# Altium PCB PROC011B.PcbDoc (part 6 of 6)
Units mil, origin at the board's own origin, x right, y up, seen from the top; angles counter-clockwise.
Board outline 3304 x 2569 mil, 6 copper layers (TOP, L2-GND1, L3-GND/SIG, L4-GND/SIG, L5-GND2, BOTTOM), stack 55.77 mil thick; 376 components, 289 nets, 1284 pads, 1755 vias.

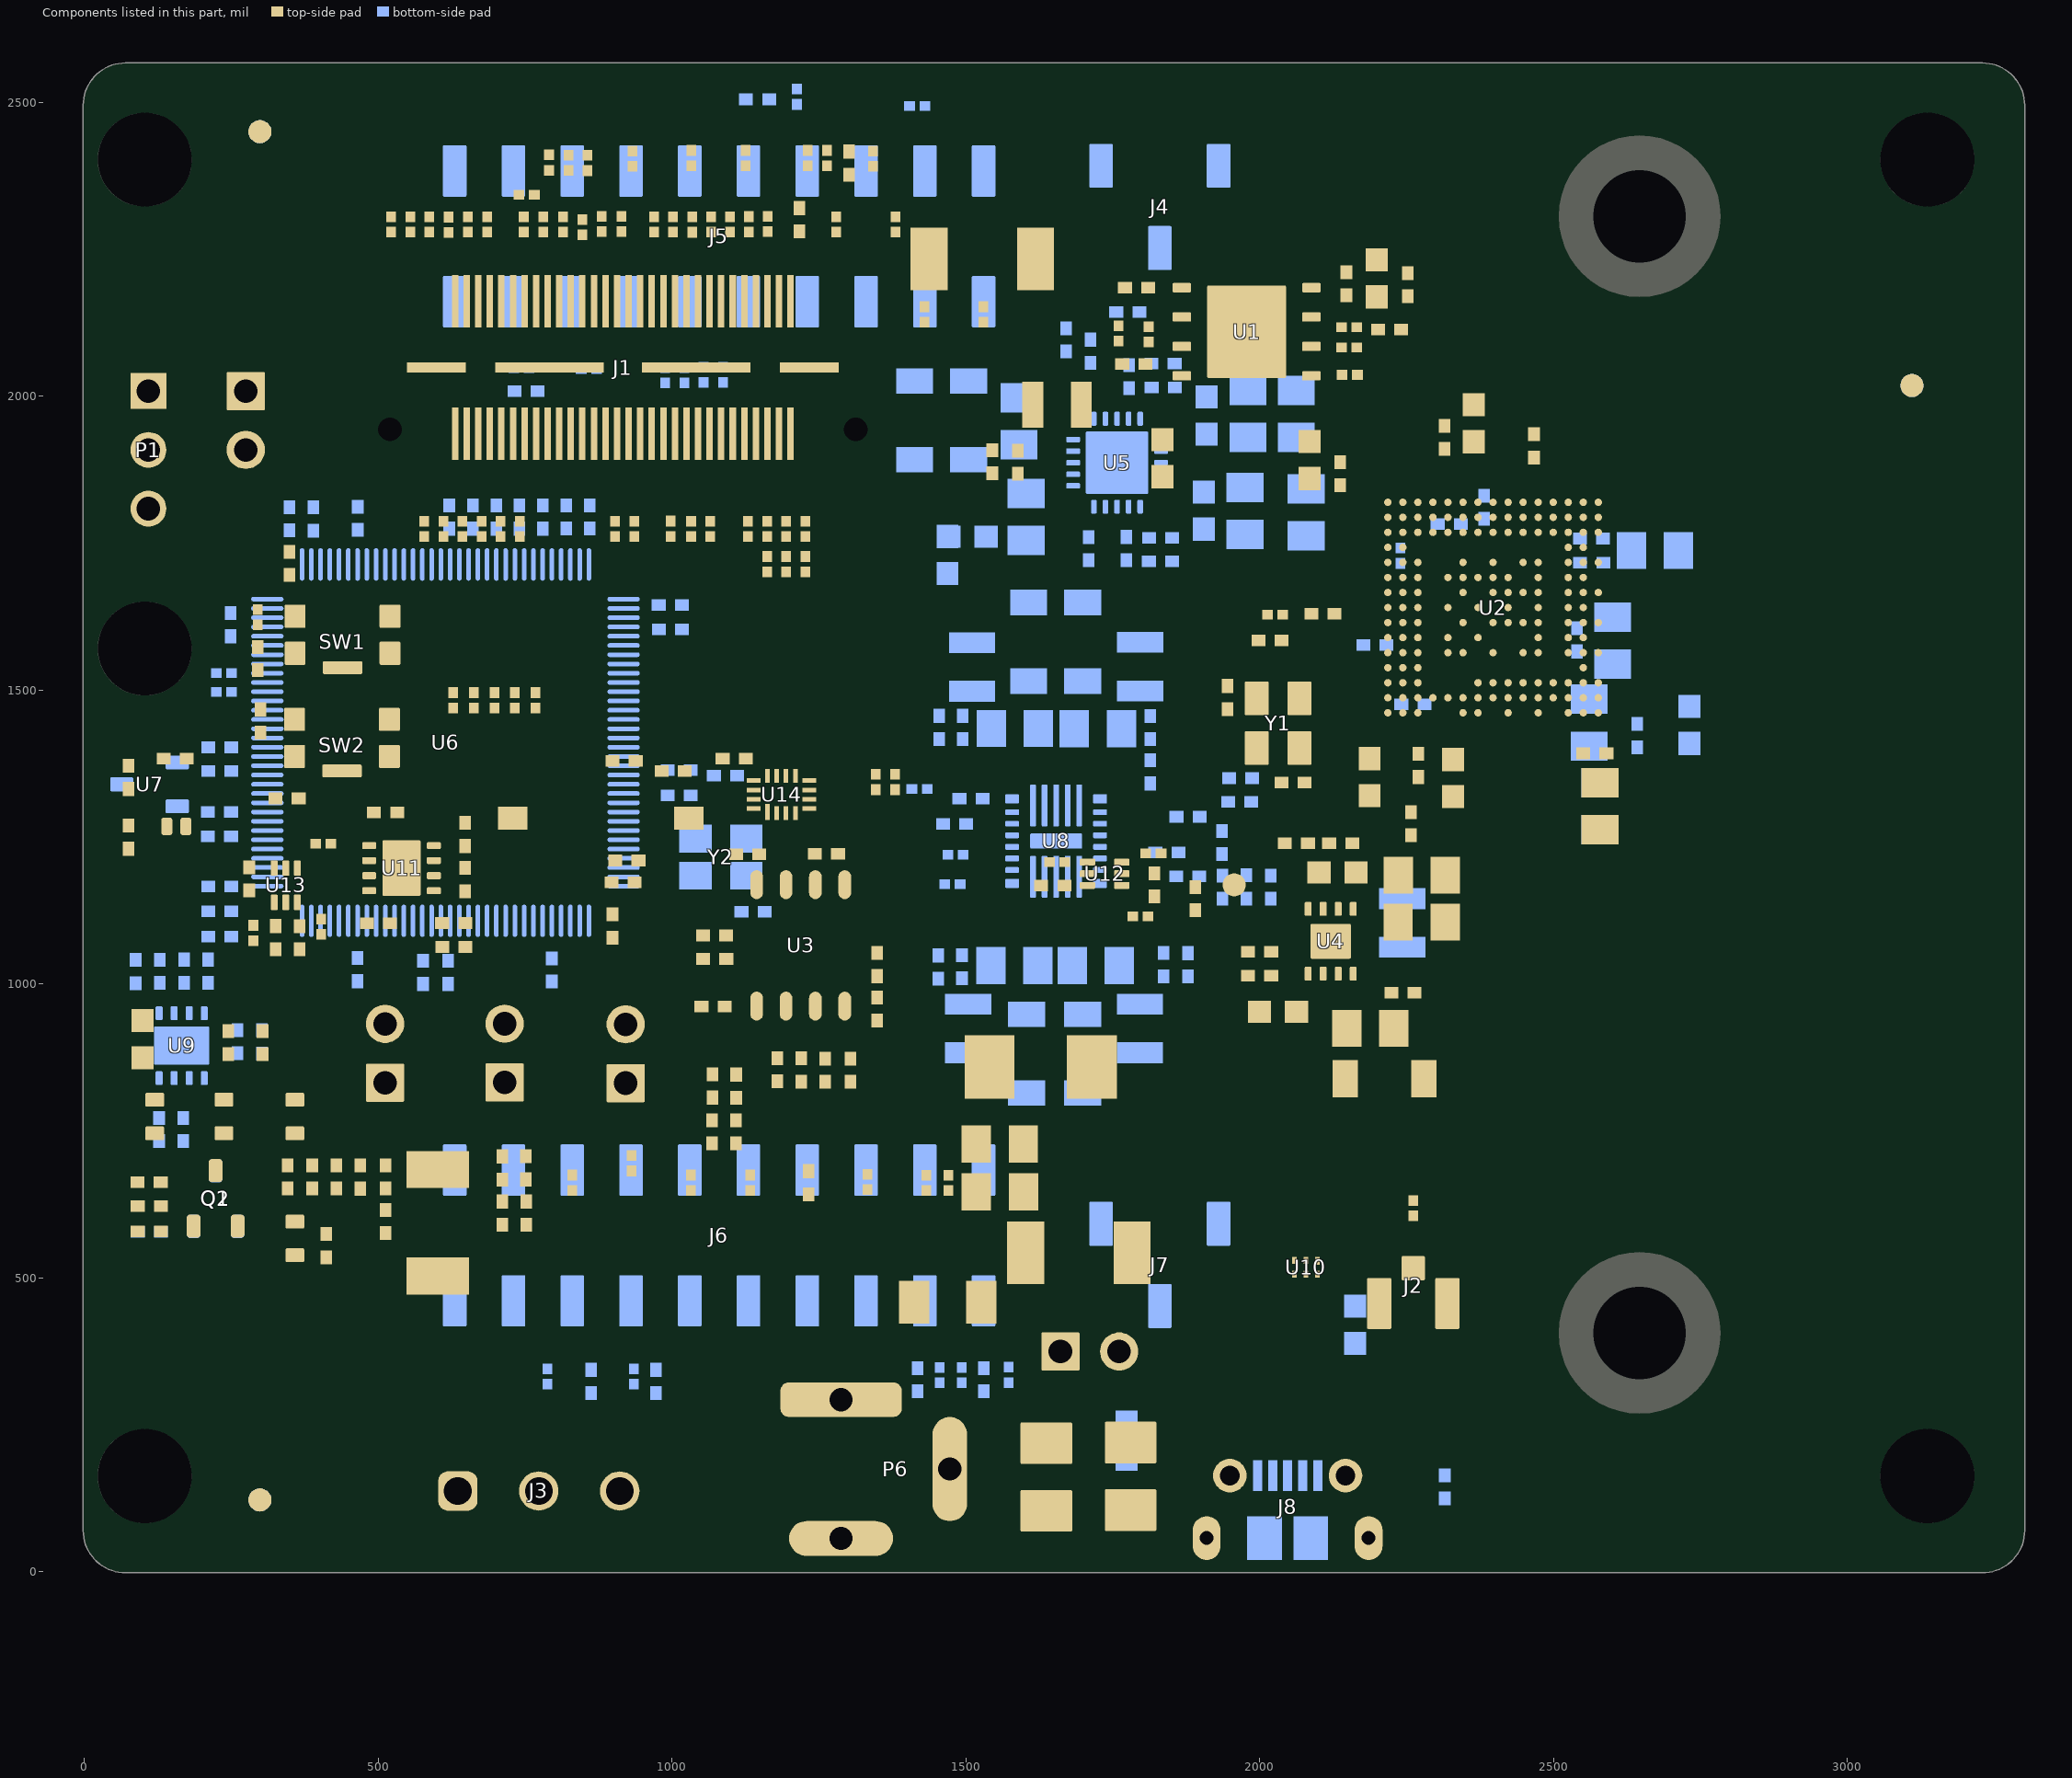
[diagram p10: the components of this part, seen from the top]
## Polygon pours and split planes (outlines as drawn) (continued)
NetR42_2 on TOP "TOP-UNNAMED_41_RESISTOR_I116_2" (solid, pour order 971): 1894.98,2096.48 1842.88,2096.48 1842.88,2072.88 1894.98,2072.88 1894.98,2096.48
NetR44_1 on TOP "TOP-UNNAMED_41_RESISTOR_I117_1" (solid, pour order 970): 2112.88,2096.48 2060.78,2096.48 2060.78,2072.88 2112.88,2072.88 2112.88,2096.48
NetR45_1 on TOP "TOP-UNNAMED_41_RESISTOR_I118_1" (solid, pour order 969): 2112.88,2046.48 2060.78,2046.48 2060.78,2022.88 2112.88,2022.88 2112.88,2046.48
NetR39_2 on TOP "TOP-UNNAMED_41_RESISTOR_I119_2" (solid, pour order 968): 1894.98,2146.48 1842.88,2146.48 1842.88,2122.88 1894.98,2122.88 1894.98,2146.48
NetR40_1 on TOP "TOP-UNNAMED_41_RESISTOR_I120_1" (solid, pour order 967): 2112.88,2146.48 2060.78,2146.48 2060.78,2122.88 2112.88,2122.88 2112.88,2146.48
NetJ1_1 on TOP "TOP-UNNAMED_43_QSH03001XD_I1_1" (solid, pour order 966): 466 vertices, not listed, extent 1177.39,1891 1453.7,2296
NetF1_2 on TOP "TOP-UNNAMED_39_FUSE_I161_1" (solid, pour order 965): 146 vertices, not listed, extent 1188.75,269 1438.25,500
MCU_5V on TOP "TOP-MCU_5V" (solid, pour order 962): 124 vertices, not listed, extent 521.77,668 690.75,772
PMIC_2V3 on TOP "TOP-PMIC_2V3" (solid, pour order 957): 258 vertices, not listed, extent 1843.65,791.5 2266.05,1059.2
NetC85_2 on TOP "TOP-UNNAMED_7_CAPNONPOLARIZED_I5_2" (solid, pour order 954): 194 vertices, not listed, extent 384.65,1079 496.19,1218
NetC26_1 on TOP "TOP-UNNAMED_39_CAPPOLARIZED_I74_1" (solid, pour order 953): 340 vertices, not listed, extent 1471.05,182.8 1838.25,913.5
TX1 on TOP "TOP-TX1" (solid, pour order 1042): 38 vertices, not listed, extent 2736.95,1172.87 3184.98,1231.93
TX2 on TOP "TOP-TX2" (solid, remove dead copper, pour order 1043): 38 vertices, not listed, extent 2736.95,873.67 3184.98,932.73
PMIC_1V2 on TOP "TOP-PMIC_1V2" (solid, pour order 979): 40 vertices, not listed, extent 1988.35,1837.9 2151.05,1900.5
GND on TOP "TOP-GND 5" (solid, pour order 981): 38 vertices, not listed, extent 2736.95,1823.37 3184.98,1882.43
GND on TOP "TOP-GND 4" (solid, pour order 978): 38 vertices, not listed, extent 2736.95,1449.37 3184.98,1508.43
RX1 on TOP "TOP-RX1" (solid, pour order 952): 38 vertices, not listed, extent 2736.95,1748.57 3184.98,1807.63
RX2 on TOP "TOP-RX2" (solid, pour order 950): 38 vertices, not listed, extent 2736.95,1673.77 3184.98,1732.83
RX3 on TOP "TOP-RX3" (solid, pour order 949): 38 vertices, not listed, extent 2736.95,1598.97 3184.98,1658.03
RX4 on TOP "TOP-RX4" (solid, pour order 948): 38 vertices, not listed, extent 2736.95,1524.17 3184.98,1583.23
no net on TOP "Top Layer-No Net" (solid, pour order 951): 1734.28,2432.55 1746.09,2432.55 1769.71,2431.96 2395.15,2431.96 2418.77,2432.55 2430.58,2432.55 2430.58,2438.45 2418.77,2438.45 2395.15,2439.04 1769.71,2439.04 1746.09,2438.45 1734.28,2438.45
no net on TOP "Top Layer-No Net" (solid, pour order 956): 2211.13,2344.45 2211.13,2350.35 2222.94,2350.35 2246.56,2350.94 2394.35,2350.94 2417.97,2350.35 2429.78,2350.35 2429.78,2344.45 2417.97,2344.45 2394.35,2343.86 2246.56,2343.86 2222.94,2344.45
GND on TOP "TOP-GND 1" (solid, remove dead copper, pour order 1007): 2460.75,2487 2460.75,2309 2076.75,2309 2076.75,2382 1698.75,2382 1698.75,2487 2460.75,2487
GND on L4-GND/SIG "L4-GND 4" (solid, pour order 1023): 1170 vertices, not listed, extent 1011,2201.12 1728.04,2476.59
GND on L4-GND/SIG "L4-GND 3" (solid, remove dead copper, pour order 1022): 2496 vertices, not listed, extent 16,16 3284,2549
GND on L4-GND/SIG "L4-GND 1" (solid, pour order 1020): 840 vertices, not listed, extent 2279.76,1480.82 2511.89,1757.58
GND on L4-GND/SIG "L4-GND" (solid, pour order 1019): 555 vertices, not listed, extent 486.77,2124.33 1041.63,2468.58
5V_IN on L4-GND/SIG "L4-5V_IN" (solid, remove dead copper, pour order 997): 1026 vertices, not listed, extent 437.25,327 1727.75,2363.5
AR_1V8 on L4-GND/SIG "L4-AR_1V8" (solid, pour order 986): 679 vertices, not listed, extent 2127.75,1077.15 2619.75,1752
PMIC_1V2 on L4-GND/SIG "L4-PMIC_1V2" (solid, pour order 984): 1509 vertices, not listed, extent 1750.75,1574 2517.75,2258.4
NetC85_2 on L4-GND/SIG "L4-UNNAMED_7_CAPNONPOLARIZED_I5_2" (solid, pour order 955): 96 vertices, not listed, extent 371.65,1146.2 422.25,1236.1
5V_UNREG on L4-GND/SIG "POWER2-No Net" (solid, remove dead copper, pour order 1046): 44 vertices, not listed, extent 1441.77,315 1865.48,1542.5
GND on L4-GND/SIG "Top Layer-No Net" (solid, pour order 116): 43 vertices, not listed, extent 1376.03,1265.26 1898.12,2227.86
GND on BOTTOM "BOTTOM-GND 4" (solid, remove dead copper, pour order 1035): 2173 vertices, not listed, extent 1878.77,15.7 3284.85,2549.9
GND on BOTTOM "BOTTOM-GND 7" (solid, pour order 1040): 307 vertices, not listed, extent 1568.8,1267.5 1736.9,1546
GND on BOTTOM "BOTTOM-GND 6" (solid, pour order 1039): 239 vertices, not listed, extent 1567.7,919.3 1734.3,1218.3
GND on BOTTOM "BOTTOM-GND 5" (solid, pour order 1037): 98 vertices, not listed, extent 1882.75,1982.35 2102.75,2147.5
GND on BOTTOM "BOTTOM-GND 3" (solid, pour order 1034): 510 vertices, not listed, extent 1703,307 2093.73,726.5
GND on BOTTOM "BOTTOM-GND 2" (solid, pour order 1033): 124 vertices, not listed, extent 1364.75,1971.5 1621.05,2069.85
GND on BOTTOM "BOTTOM-GND 1" (solid, pour order 1013): 2497.25,2153.5 2796.25,2153.5 2796.25,2455.5 2497.25,2455.5 2497.25,2153.5
GND on BOTTOM "BOTTOM-GND" (solid, pour order 1008): 21 vertices, not listed, extent 2421.7,31.02 3277.75,827.5
5V_UNREG on BOTTOM "BOTTOM-5V_UNREG 3" (solid, pour order 1005): 200 vertices, not listed, extent 1525.15,1267.5 1619.3,1475.26
5V_UNREG on BOTTOM "BOTTOM-5V_UNREG 2" (solid, pour order 1004): 209 vertices, not listed, extent 1687.75,1267.5 1787.85,1475.66
5V_UNREG on BOTTOM "BOTTOM-5V_UNREG 1" (solid, pour order 1003): 202 vertices, not listed, extent 1686.8,1002.3 1813.8,1218.5
5V_UNREG on BOTTOM "BOTTOM-5V_UNREG" (solid, remove dead copper, pour order 1002): 183 vertices, not listed, extent 1514.45,1002.3 1620.75,1218.3
PMICOUT_3V3 on BOTTOM "BOTTOM-PMICOUT_3V3" (solid, pour order 999): 176 vertices, not listed, extent 1453.77,1563.04 1642.75,1711.5
AR_1P3_RF1 on BOTTOM "BOTTOM-AR_1P3_RF1" (solid, pour order 992): 937 vertices, not listed, extent 1821.75,1607 2812.73,1963.7
AR_1P3_RF2 on BOTTOM "BOTTOM-AR_1P3_RF2" (solid, pour order 990): 1059 vertices, not listed, extent 1818.8,1431.4 2987.75,2118
AR_1V8 on BOTTOM "BOTTOM-AR_1V8 1" (solid, pour order 988): 124 vertices, not listed, extent 2147.75,1120 2286.65,1256.3
AR_1V8 on BOTTOM "BOTTOM-AR_1V8" (solid, pour order 987): 91 vertices, not listed, extent 2526.75,1593 2629.75,1638.98
PMIC_1V2 on BOTTOM "BOTTOM-PMIC_1V2" (solid, pour order 983): 299 vertices, not listed, extent 1663,1563 1950.75,1709.25
AR_VOUT_PA on BOTTOM "BOTTOM-AR_VOUT_PA" (solid, pour order 976): 138 vertices, not listed, extent 2539.75,1315 2755.75,1427
PMIC_1V8 on BOTTOM "BOTTOM-PMIC_1V8" (solid, remove dead copper, pour order 973): 1183 vertices, not listed, extent 1339.97,801.5 1702.75,1952.5
MCU_5V on BOTTOM "BOTTOM-MCU_5V 1" (solid, pour order 964): 98 vertices, not listed, extent 1868.75,510 1993.75,651
MCU_5V on BOTTOM "BOTTOM-MCU_5V" (solid, pour order 961): 149 vertices, not listed, extent 517.75,626.5 686.75,759.5
PMIC_2V3 on BOTTOM "BOTTOM-PMIC_2V3 1" (solid, pour order 960): 146 vertices, not listed, extent 2140.55,968.7 2284.45,1079.3
PMIC_2V3 on BOTTOM "BOTTOM-PMIC_2V3" (solid, pour order 958): 127 vertices, not listed, extent 1662.75,791 1947.35,900.66
GND on L3-GND/SIG "L3-GND 7" (solid, remove dead copper, pour order 1029): 3094 vertices, not listed, extent 16,16 3284,2549
GND on L3-GND/SIG "L3-GND 6" (solid, pour order 1028): 2622 vertices, not listed, extent 1431.33,501.13 2744.73,1845.59
GND on L3-GND/SIG "L3-GND 5" (solid, pour order 1027): 744 vertices, not listed, extent 991.89,593.02 1910.98,1006.2
GND on L3-GND/SIG "L3-GND 4" (solid, pour order 1026): 147 vertices, not listed, extent 231.09,1463.5 468.73,1691.74
GND on L3-GND/SIG "L3-GND 3" (solid, pour order 1025): 344 vertices, not listed, extent 1505.88,1776.02 1989.21,2041.98
GND on L3-GND/SIG "L3-GND 2" (solid, pour order 1024): 146 vertices, not listed, extent 1858.06,1991.53 2249.71,2152.58
GND on L3-GND/SIG "L3-GND 1" (solid, pour order 1012): 2487.75,562.5 2787.75,562.5 2787.75,262.5 2487.75,262.5 2487.75,562.5
GND on L3-GND/SIG "L3-GND" (solid, pour order 1011): 2507.75,2437.5 2777.75,2437.5 2777.75,2182.5 2597.75,2182.5 2507.75,2272.5 2507.75,2437.5
MCU_5V on L3-GND/SIG "L3-MCU_5V" (solid, pour order 963): 517 vertices, not listed, extent 507.75,406 1962.23,755.48
GND on L2-GND1 "L2-GND 1" (solid, pour order 1010): 2527.25,529.5 2527.25,282.5 2772.25,282.5 2772.25,529.5 2527.25,529.5
GND on L2-GND1 "L2-GND" (solid, pour order 1009): 2524.75,2427 2524.75,2180 2769.75,2180 2769.75,2427 2524.75,2427
GND on L2-GND1 "L5-GND" (solid, remove dead copper, pour order 1018): 553 vertices, not listed, extent 16,16 3284,2549
GND on L5-GND2 "L5-GND" (solid, remove dead copper, pour order 1017): 553 vertices, not listed, extent 16,16 3284,2549
no net on Mechanical 6 Ass bot (solid): 3150.95,2033.2 ccw(c3108.95,2033.2) 3108.95,2075.2 ccw(c3108.95,2033.2) 3066.95,2033.2 ccw(c3108.95,2033.2) 3108.95,1991.2 ccw(c3108.95,2033.2) 3150.95,2033.2
no net on Mechanical 6 Ass bot (solid): 340.75,122 ccw(c298.75,122) 298.75,164 ccw(c298.75,122) 256.75,122 ccw(c298.75,122) 298.75,80 ccw(c298.75,122) 340.75,122
no net on Mechanical 6 Ass bot (solid): 340.75,2450 ccw(c298.75,2450) 298.75,2492 ccw(c298.75,2450) 256.75,2450 ccw(c298.75,2450) 298.75,2408 ccw(c298.75,2450) 340.75,2450
no net on Mechanical 5 Ass top (solid): 340.75,2450 ccw(c298.75,2450) 298.75,2492 ccw(c298.75,2450) 256.75,2450 ccw(c298.75,2450) 298.75,2408 ccw(c298.75,2450) 340.75,2450
no net on Mechanical 5 Ass top (solid): 3152.65,2018.46 ccw(c3110.65,2018.46) 3110.65,2060.46 ccw(c3110.65,2018.46) 3068.65,2018.46 ccw(c3110.65,2018.46) 3110.65,1976.46 ccw(c3110.65,2018.46) 3152.65,2018.46
no net on Mechanical 5 Ass top (solid): 340.75,122 ccw(c298.75,122) 298.75,164 ccw(c298.75,122) 256.75,122 ccw(c298.75,122) 298.75,80 ccw(c298.75,122) 340.75,122

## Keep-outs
TOP:
  circle w10: c102.75,2402.5 r92.09
  circle w10: c102.75,1570.6 r92.09
  circle w10: c102.75,162.5 r92.09
  circle w10: c3136.31,2402.5 r92.09
  circle w10: c3136.31,162.5 r92.09
L2-GND1:
  circle w10: c3136.31,2402.5 r100.82
  circle w10: c3136.31,162.5 r100.82
  circle w10: c3136.31,2402.5 r100.82
  circle w10: c1312.65,1943.64 r44.95
  circle w10: c520.13,1943.64 r44.95
L3-GND/SIG:
  circle w10: c3136.31,162.5 r100.82
  circle w10: c3136.31,2402.5 r100.82
L4-GND/SIG:
  circle w10: c1312.65,1943.64 r44.95
  circle w10: c3136.31,162.5 r100.82
  circle w10: c3136.31,2402.5 r100.82
L5-GND2:
  circle w10: c1312.65,1943.64 r44.95
  circle w10: c520.13,1943.64 r44.95
  circle w10: c3136.31,2402.5 r100.82
  circle w10: c3136.31,162.5 r100.82
BOTTOM:
  circle w10: c3136.31,162.5 r92.09
  circle w10: c3136.31,2402.5 r92.09
  circle w1: c3110.08,2018.14 r44
Keep-Out Layer:
  text "KEEP OUT LAYER" at -1318.01,-1032.33 h75

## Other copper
TOP:
  text "TOP" at -1316.15,-1038.69 h75
L2-GND1:
  text "LAYER-2 GND1" at -1293.22,-1034.39 h75
L3-GND/SIG:
  text "LAYER-3 GND/SIGNAL" at -1349.73,-1034.31 h75
L4-GND/SIG:
  text "LAYER-4 GND/SIGNAL" at -1322.23,-1041.27 h75
L5-GND2:
  text "LAYER-5 GND2" at -1308.33,-1043.01 h75
BOTTOM:
  text "BOTTOM" at -1318.46,-1042.03 h75

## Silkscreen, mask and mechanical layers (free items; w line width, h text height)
Top Overlay:
  lines w10: 176.28,1919.69 179.6,1919.69 193.53,1905.76 193.53,1794.32 187.71,1800.14 200.17,1800.14 194.35,1794.32
  lines w30: 1378.75,904.5 1378.75,818 1459.85,818 ; 1378.75,1094.5 1378.75,1274.5 ; 1382.75,1830 1382.75,2242 ; 1700.75,2258 2146.75,2258 ; 1786.25,818 2088.75,818 ; 2268.75,2258 2474.75,2258 ; 2770.75,1968 2770.75,2182
  text "HD_CONN" at 467.92,2015.1 h30 r90
  text "VPP_1P7" at 381.32,1862.65 h30 r90
  text "1642-EVM" at 813.79,1694.33 h30
  text "GND" at 209.45,1680.5 h30 r90
  text "PROC011" at 775,1637.52 h30
  text "REV B" at 969.45,1635.95 h30
  text "GPIO1" at 620.25,1543 h30 r90
  text "ON" at 1079.14,1311 h30 r90
  text "NRST" at 615.01,1295.07 h30 r90
  text "SPI" at 709,1164 h30 r90
  text "CAN" at 1079.14,1153 h30 r90
  text "SOP0" at 1025.49,883.72 h30 r90
  text "5V" at 385.25,854.5 h30 r90
  text "NERR_OUT" at 211.42,848.5 h30 r90
  text "SOP1" at 821.68,840.86 h30 r90
  text "SOP2" at 615.55,835.13 h30 r90
  text "NRST" at 404.16,399.06 h30 r90
  text "5V_IN" at 1194.75,354 h30 r90
  text "GND" at 790.25,294 h30 r90
  text "CAN_L" at 1066.42,227.5 h30 r90
  text "CAN_H" at 542.42,226.5 h30 r90
  text "USB" at 2011.93,198.27 h30
  text "SILKSCREEN TOP" at -1339.97,-1029.03 h60
Bottom Overlay:
  drawing of 8192 lines, arcs and shapes, not listed
  text "GND" at 1745.25,2556 h30 r90
  text "GND" at 1845.25,2556 h30 r90
  text "3V3" at 1943.47,2549.66 h30 r90
  text "GND" at 596.45,2529.6 h30 r90
  text "20" at 1634.19,2423.68 h30 r90
  text "2" at 552.36,2404.47 h30 r90
  text "19" at 1638.64,2210.67 h30 r90
  text "1" at 544.91,2180.78 h30 r90
  text "P1" at 132.79,2073.5 h30
  text "P7" at 396.41,2020 h30
  text "P4" at 955.85,1005.8 h30
  text "P3" at 537.9,1001.27 h30
  text "P2" at 736.23,1000.15 h30
  text "GND" at 790.25,886 h30 r90
  text "GND" at 1845.25,776 h30 r90
  text "GND" at 1735.25,771 h30 r90
  text "20" at 1641.82,729.19 h30 r90
  text "2" at 553.44,705.94 h30 r90
  text "19" at 1656.65,524.84 h30 r90
  text "1" at 545.99,482.25 h30 r90
  text "P6" at 1317.41,338.79 h30
  text "P5" at 1877.7,327.72 h30
  text "J3" at 538.18,135.69 h30
  text "SILKSCREEN BOTTOM" at -1330.97,-1032.41 h75
Top Paste:
  text "SOLDERPASTE TOP" at -1322.76,-1029.77 h75
Bottom Paste:
  text "SOLDERPASTE BOTTOM" at -1315.43,-1031.21 h75
Top Solder:
  text "SOLDERMASK TOP" at -1325.23,-1033.37 h75
Bottom Solder:
  text "SOLDERMASK BOTTOM" at -1292.25,-1013.98 h75
OUTLINE:
  lines w4: 0,70 ccw(c70,70) 70,0 3230,0 ccw(c3230,70) 3300,70 3300,2495 ccw(c3230,2495) 3230,2565 70,2565 ccw(c70,2495) 0,2495 0,70
Board Dimensions:
  text "AT 4 PLACES" at -810,-280 h75
Mechanical 5 Ass top:
  lines w6: 163,2270 163,2286 174,2297 355,2297 405,2247 741,2247 747,2253 747,2256 ; 355.14,2202 420,2202 435,2217 897.05,2217 912,2231.95 912,2254 ; 974,2330 974,2349.96 985.04,2361 1276.02,2361 1291.02,2346 1361,2346 1376,2361 1376,2381 1391,2396 ; 1162.65,2337 1162.65,2337.65 1171,2346 1256.78,2346 1269.78,2333 1574,2333 1604,2363 1604,2371 ; 2111,2139 2111,2127.39 2113.39,2125
  lines w10: -2151.07,-1099.34 4448.93,-1099.34 ; -2151.07,-896 4450.93,-896 ; -2151.07,-692.67 -2151.07,-1302.67 1853.93,-1302.67 4450.93,-1302.67 4450.93,-692.67 -2150.57,-692.67 -2150.57,-1302.67 -575.07,-1302.67 ; 313.93,-1302.67 313.93,-692.67 ; 1580.93,-896 1580.93,-692.67 ; 2420.93,-896 2420.93,-692.67 ; 3042.93,-1309.17 3042.93,-1106.34
  text "COMPONENTS MARKED 'DNP' SHOULD NOT BE POPULATED." at -1592.26,2897.89 h60
  text "ASSEMBLY VARIANT:" at -1592.76,2782.39 h60
  text ".VariantName" at -556.76,2782.39 h60
  text "PCB VIEWED FROM TOP SIDE" at -2087.57,-824.84 h60
  text "BOARD #:" at 388.93,-824.84 h60
  text ".PRJ_Number" at 934.43,-824.84 h60
  text "REV:" at 1778.93,-824.84 h60
  text ".PCB_Rev" at 2070.43,-824.84 h60
  text "SVN REV:" at 2616.93,-824.84 h60
  text ".VersionControl_RevNumber" at 3122.93,-824.84 h60
  text "Assembly TOP" at -1818.81,-1016.17 h60
  text "TID #:" at 388.93,-1028.17 h60
  text ".TID" at 934.43,-1028.17 h60
  text "PLOT NAME =" at -2087.57,-1233.51 h60
  text ".plot_File_Name" at -1282.07,-1233.51 h35
  text "GENERATED    :" at 390.93,-1233.51 h60
  text ".Print_Date" at 1260.43,-1233.51 h60
  text ".Print_Time" at 1989.43,-1233.51 h60
  text "TEXAS INSTRUMENTS" at 3253.93,-1233.51 h60
Mechanical 6 Ass bot:
  lines w10: -2151.07,-896 4450.93,-896 ; -2149.07,-1099.34 4450.93,-1099.34 ; -743.07,-1309.17 -743.07,-1106.34 ; -121.07,-896 -121.07,-692.67 ; 718.93,-896 718.93,-692.67 ; 1985.93,-1302.67 1985.93,-692.67 ; 2874.93,-1302.67 4450.43,-1302.67 4450.43,-692.67 -2151.07,-692.67 -2151.07,-1302.67 445.93,-1302.67 4450.93,-1302.67 4450.93,-692.67
  text "COMPONENTS MARKED 'DNP' SHOULD NOT BE POPULATED." at 4243.43,-486.67 h60
  text ".VariantName" at 3199.43,-602.67 h60
  text "ASSEMBLY VARIANT:" at 4238.43,-602.67 h60
  text ".VersionControl_RevNumber" at -823.07,-824.84 h60
  text "SVN REV:" at -317.07,-824.84 h60
  text ".PCB_Rev" at 229.43,-824.84 h60
  text "REV:" at 520.93,-824.84 h60
  text ".PRJ_Number" at 1365.43,-824.84 h60
  text "BOARD #:" at 1910.93,-824.84 h60
  text "PCB VIEWED FROM BOTTOM SIDE" at 4387.43,-824.84 h60
  text ".TID" at 1365.43,-1028.17 h60
  text "TID #:" at 1910.93,-1028.17 h60
  text "ASSEMBLY BOTTOM" at 4003,-1028 h60
  text "TEXAS INSTRUMENTS" at -954.07,-1233.51 h60
  text ".Print_Time" at 310.43,-1233.51 h60
  text ".Print_Date" at 1039.43,-1233.51 h60
  text "GENERATED    :" at 1908.93,-1233.51 h60
  text ".plot_File_Name" at 3581.93,-1233.51 h35
  text "PLOT NAME =" at 4387.43,-1233.51 h60
M9 Title Sheet:
  lines w10: -2351.2,871.62 -2151.2,871.62 ; -2351.2,3246.62 -2151.2,3246.62 ; -2351.2,5621.62 -2151.2,5621.62 ; 148.8,-1503.38 148.8,-1303.38 ; 148.8,7796.62 148.8,7996.62 ; 2648.8,-1503.38 2648.8,-1303.38 ; 2648.8,7796.62 2648.8,7996.62 ; 4461.3,-1303.38 4461.3,-693.38 9443.8,-693.38 ; 5148.8,-1503.38 5148.8,-1303.38 ; 5148.8,7796.62 5148.8,7996.62 ; 7648.8,-1503.38 7648.8,-1303.38 ; 7648.8,7796.62 7648.8,7996.62 ; 9443.8,-1303.38 9443.8,-693.38 ; 9443.8,-993.38 12443.8,-993.38 ; 9443.8,-393.38 12443.8,-393.38 ; 9444.8,200.62 12444.8,200.62 ; 10148.8,-1503.38 10148.8,-1303.38 ; 10148.8,7796.62 10148.8,7996.62 ; 10948.8,-1293.38 10948.8,-693.38 ; 12443.8,-693.38 9443.8,-693.38 ; 12443.8,-93.38 9443.8,-93.38 ; 12448.8,-103.38 12448.8,-1303.38 ; 12448.8,701.12 9444.8,701.12 9443.8,701.12 9443.8,200.62 9443.8,-93.38 ; 12448.8,871.62 12648.8,871.62 ; 12448.8,3246.62 12648.8,3246.62 ; 12448.8,5621.62 12648.8,5621.62 ; 9443.8,-693.38 9443.8,-93.38 ; 12448.8,-1303.38 12448.8,7796.62 -2151.2,7796.62 -2151.2,-1303.38 12448.8,-1303.38 ; -2351.2,-1503.38 -2351.2,7996.62 12648.8,7996.62 12648.8,-1503.38 -2351.2,-1503.38
  text "1" at -1119.86,7866.62 h70
  text "2" at 1375.8,7866.62 h70
  text "3" at 3865.14,7866.62 h70
  text "4" at 6371.81,7866.62 h70
  text "5" at 8870.8,7866.62 h70
  text "6" at 11375.8,7866.62 h70
  text "A" at -2276.2,6723.62 h70
  text "A" at 12523.8,6723.62 h70
  text "B" at -2276.2,4343.62 h70
  text "B" at 12523.8,4343.62 h70
  text "C" at -2276.2,1968.62 h70
  text "C" at 12523.8,1968.62 h70
  text "PROJECT TITLE:" at 9483.8,107.62 h45
  text ".PRJ_Title" at 9533.8,-25.71 h50
  text "DESIGNED FOR:" at 9483.8,-193.38 h45
  text ".PRJ_Customer" at 9533.8,-333.38 h70
  text "D" at -2276.2,-401.38 h70
  text "D" at 12523.8,-401.38 h70
  text "FILE NAME:" at 9483.8,-493.38 h45
  text ".PCB_File_Name_No_Path" at 9533.8,-613.38 h70
  text "Texas Instruments (TI) and/or its licensors do not warrant the accuracy or completeness of this specification" at 4514.3,-775.22 h45
  text "ENGINEER:" at 9483.8,-783.38 h45
  text "LAYOUT BY:" at 10988.8,-783.38 h45
  text "or any information contained therein. TI and/or its licensors do not warrant that this design will meet" at 4469.31,-887.88 h45
  text ".PRJ_Engineer" at 9533.8,-938.37 h70
  text ".PCB_Layout" at 11039.3,-938.37 h70
  text "the specifications, will be suitable for your application or fit for any particular purpose, or will operate in" at 4469.31,-1000.55 h45
  text "ALTIUM DESIGNER VERSION:" at 10988.8,-1093.38 h45
  text "an implementation. TI and/or its licensors do not warrant that the design is production worthy. You should" at 4469.31,-1113.21 h45
  text "completely validate and test your design implementation to confirm the system functionality for your application." at 4514.3,-1225.88 h45
  text ".print_Scale" at 9533.8,-1226.71 h70
  text ".Application_BuildNumber" at 11039.3,-1226.71 h70
  text "1" at -1119.86,-1433.38 h70
  text "2" at 1375.8,-1433.38 h70
  text "3" at 3865.14,-1433.38 h70
  text "4" at 6371.81,-1433.38 h70
  text "5" at 8870.8,-1433.38 h70
  text "6" at 11375.8,-1433.38 h70
LOGO_HOT:
  drawing of 189 lines, arcs and shapes, not listed
  text "DESIGN INFORMATION" at 10521.82,6186.29 h60
  text "MIL" at 11183,6056 h60
  text "MIN. TRACK WIDTH:" at 9877.26,6054.17 h60
  text "4" at 10973.5,6054.17 h60
  text "4" at 10965.36,5957.06 h60
  text "MIL" at 11182.26,5931 h60
  text "MIN. CLEARANCE:" at 9877.26,5930.04 h60
  text "MIL" at 11185,5807 h60
  text "MIN. VIA PAD SIZE:" at 9877.26,5805.92 h60
  text "13.77" at 10873,5798 h60
  text "0.05mm (2MIL)" at 10572.26,5676.02 h60
  text "MINIMUM ANNULAR RING" at 9548.03,5667.79 h60
  text "EXTERNAL" at 11280.26,5667.79 h60
  text "PER" at 9748.03,5557.67 h60
  text "IPC-D-275 CLASS 2 LEVEL C" at 9968.03,5557.66 h60
  text "MIL, HOLES" at 11456.26,5457.19 h60
  text "+/-" at 11063.8,5448.6 h60
  text "+/-" at 11917.8,5448.6 h60
  text "REGISTRATION TOLERANCES:" at 9548.03,5447.54 h60
  text "METAL" at 10747.8,5447.54 h60
  text "2" at 11324,5447.54 h60
  text "3" at 12157,5447.54 h60
  text "MIL" at 12273.26,5447.54 h60
  text "HOLE SIZE TOLERANCE (UNLESS OTHERWISE SPECIFIED):" at 9548.03,5349.22 h60
  text "+/-" at 11917.8,5346.35 h60
  text "3" at 12157,5345.29 h60
  text "MIL" at 12273.26,5345.29 h60
  text "MATERIAL:" at 9473.26,5207.64 h60
  text "FR-4 High Tg" at 10459.7,5079.12 h60
  text "X" at 11197.39,5075.36 h60
  text "FR-408" at 9894.26,5066.61 h60
  text "OTHER" at 11382.26,5066.61 h60
  text "REFER STACKUP" at 11710.91,5051.35 h60
  text "THICKNESS:" at 9489.68,4927.16 h60
  text "X" at 10000.66,4924.28 h60
  text "56.21 MIL (1.43mm) +/-10%" at 10100.96,4922.18 h60
  text "OTHER" at 11499.26,4915.36 h60
  text "TOLERANCE:" at 9548.03,4777.04 h60
  text "X" at 10396.26,4777.04 h60
  text "ANSI IPC-6012 TYPE 3 CLASS 2" at 10574.28,4777.04 h60
  text "OTHER +/-" at 10574.26,4632.85 h60
  text "BOW & TWIST:" at 9548.03,4487.66 h60
  text "X" at 10396.26,4487.66 h60
  text "ANSI IPC-6012 TYPE 3 CLASS 2" at 10574.28,4487.66 h60
  text "OTHER +/-" at 10574.26,4340.97 h60
  text "DRILLING:" at 9473.26,4210.35 h60
  text "NC_DRILL FILES" at 11234.26,4105.16 h60
  text "REFERENCE:" at 9548.03,4101.22 h60
  text "X" at 10205.26,4101.13 h60
  text "AS SHOWN" at 10383.26,4101.22 h60
  text "X" at 11106.26,4101.22 h60
  text "OTHER" at 11532.26,3958.97 h60
  text "PTH COPPER THICKNESS:" at 9547.71,3955.44 h60
  text "X" at 10686.94,3955.44 h60
  text "20-30 um" at 10814.94,3955.44 h60
  text "BOARD FINISH:" at 9473.26,3807.85 h60
  text "SILKSCREEN:" at 9628.48,3697.72 h60
  text "X" at 10586.26,3697.72 h60
  text "TOP" at 10703.26,3697.72 h60
  text "X" at 11096.26,3697.72 h60
  text "BOTTOM" at 11214.26,3697.72 h60
  text "SILKSCREEN COLOR:" at 9628.48,3542.53 h60
  text "X" at 10585.26,3542.53 h60
  text "WHITE" at 10703.26,3542.53 h60
  text "OTHER" at 11214.26,3542.53 h60
  text "GREEN" at 10834.26,3399.08 h60
  text "OTHER" at 11452.26,3399.08 h60
  text "X" at 11296.74,3395.1 h60
  text "RED" at 11875.95,3395.11 h60
  text "SOLDER RESIST COLOR:" at 9628.48,3392.22 h60
  text "X" at 10716.26,3244.83 h60
  text "MATTE" at 10834.26,3244.83 h60
  text "SEMI-GLOSS" at 11451.8,3244.19 h60
  text "IMMERSION GOLD (ENIG)" at 10534.26,3072.06 h60
  text "ENEPIG" at 11871.8,3064.84 h60
  text "SURFACE FINISH:" at 9473.26,3063.84 h60
  text "IMM SILVER" at 11653,2932 h60
  text "IMM. TIN/SILVER OR EQUIV" at 9802.8,2926.52 h60
  text "X" at 11058.66,2926.28 h60
  text "OTHER" at 11234.26,2922.59 h60
  text "ARRAY/PANEL:" at 9473.26,2767.21 h60
  text "CUT AND TRIM PER M1 BOARD OUTLINE" at 10534.26,2758.99 h60
  text "X" at 10355.66,2746.28 h60
  text "N.C. ROUTE" at 10534.26,2623.02 h60
  text "V. SCORE" at 11400.26,2623.02 h60
  text "CERTIFICATION:" at 9473.26,2493.89 h60
  text "MATERIALS AND WORKMANSHIP FOR ALL PCBS" at 10198.26,2493.89 h60
  text "TO MEET OR EXCEED THE REQUIREMENTS OF:" at 10198.26,2399.83 h60
  text "X" at 9835.77,2271.2 h60
  text "ANSI IPC-A-600F CLASS ->" at 9963.76,2271.2 h60
  text "X" at 11611.77,2271.2 h60
  text "2" at 11721.76,2271.2 h60
  text "1" at 11406.76,2269.7 h60
  text "3" at 12075.76,2269.7 h60
  text "X" at 10647.77,2123.51 h60
  text "RoHS" at 10775.76,2123.51 h60
  text "OTHER" at 11420.16,2123.51 h60
  text "PER ORDER" at 11817.22,2123.51 h60
  text "ALL BOARDS MUST MEET OR EXCEED UL94-V0 REQUIREMENTS." at 9500.8,1969.69 h60
  text "PCB MUST BEAR THE UL94V-0 UL REGISTERED MATERIAL ID NUMBER" at 9500.8,1853.62 h60
  text "ADDITIONAL REQUIREMENTS:" at 9473.26,1684.2 h60
  text "MICROSECTION:" at 9548.03,1577.07 h60
  text "YES" at 10453.76,1577.07 h60
  text "REQUIRED" at 11315.26,1432.74 h60
  text "BARE BOARD ELEC. TEST:" at 9548.03,1429.88 h60
  text "NONE" at 10853.76,1429.88 h60
  text "X" at 11197.26,1429.88 h60
  text "PER ORDER" at 11907.26,1429.88 h60
  text "XX MIL VIAS REQUIRE NON-CONDUCTIVE FILL AND PLANARIZE" at 9662.75,1281.5 h59
  text "XX MIL VIAS REQUIRE CONDUCTIVE FILL AND PLANARIZE" at 9648.75,1125.5 h60
  text "OUTER XX MIL TRACES REQUIRE 50 OHM SINGLE-ENDED IMPEDANCE" at 9641.75,955.5 h58
  text "OUTER XX ML TRACES REQUIRE 100 OHM DIFFERENTIAL PAIR" at 9662.75,834.5 h60
  text "IMPEDANCE CONTROL TRACES" at 9741.75,726.5 h60
M11 Gerber Information:
  lines w10: -2151.29,-1100.49 4448.71,-1100.49 ; -2151.29,-897.15 4450.71,-897.15 ; -2151.29,-693.82 -2151.29,-1303.82 1853.71,-1303.82 4450.71,-1303.82 4450.71,-693.82 -2150.79,-693.82 -2150.79,-1303.82 -575.29,-1303.82 ; 313.71,-1303.82 313.71,-693.82 ; 1580.71,-897.15 1580.71,-693.82 ; 2420.71,-897.15 2420.71,-693.82 ; 3052.83,-1282.27 3052.83,-1079.44
  text "ALL ARTWORK VIEWED FROM TOP SIDE" at -2087.79,-825.99 h60
  text "BOARD #:" at 388.71,-825.99 h60
  text ".PRJ_Number" at 934.21,-825.99 h60
  text "REV:" at 1778.71,-825.99 h60
  text ".PCB_Rev" at 2070.21,-825.99 h60
  text "SVN REV:" at 2616.71,-825.99 h60
  text ".VersionControl_RevNumber" at 3122.71,-825.99 h60
  text "LAYER NAME =" at -2087.79,-1028.81 h60
  text "TID #:" at 388.71,-1029.32 h60
  text ".TID" at 934.21,-1029.32 h60
  text ".plot_File_Name" at -1429,-1231 h50
  text "PLOT NAME =" at -2087.79,-1234.65 h60
  text "GENERATED    :" at 390.71,-1234.65 h60
  text ".Print_Date" at 1260.21,-1234.65 h60
  text ".Print_Time" at 1989.21,-1234.65 h60
  text "TEXAS INSTRUMENTS" at 3253.71,-1234.65 h60
Mechanical 12:
  drawing of 399 lines, arcs and shapes, not listed
  text "Layer" at 3775.5,7076.5 h60
  text "Name" at 4185.41,7076.5 h60
  text "Material" at 5115.16,7076.5 h60
  text "Thickness" at 5974.92,7076.5 h60
  text "Constant" at 6624.76,7076.5 h60
  text "Board Layer Stack" at 7194.62,7076.5 h60
  text "1" at 3775.5,6956.5 h60
  text "Top Overlay" at 4185.41,6956.5 h60
  text "2" at 3775.5,6836.5 h60
  text "Top Solder" at 4185.41,6836.5 h60
  text "Solder Resist" at 5115.16,6836.5 h60
  text "0.80mil" at 5974.92,6836.5 h60
  text "0" at 6624.76,6836.5 h60
  text "3" at 3775.5,6716.5 h60
  text "TOP" at 4185.41,6716.5 h60
  text "Copper" at 5115.16,6716.5 h60
  text "1.60mil" at 5974.92,6716.5 h60
  text "4" at 3775.5,6596.5 h60
  text "Dielectric1" at 4185.41,6596.5 h60
  text "RO4835 LOPRO" at 5115.16,6596.5 h60
  text "4.00mil" at 5974.92,6596.5 h60
  text "3.66" at 6624.76,6596.5 h60
  text "5" at 3775.5,6476.5 h60
  text "L2-GND1" at 4185.41,6476.5 h60
  text "Copper" at 5115.16,6476.5 h60
  text "1.40mil" at 5974.92,6476.5 h60
  text "6" at 3775.5,6356.5 h60
  text "Dielectric2" at 4185.41,6356.5 h60
  text "370HR" at 5115.16,6356.5 h60
  text "5.67mil" at 5974.92,6356.5 h60
  text "3.9" at 6624.76,6356.5 h60
  text "7" at 3775.5,6236.5 h60
  text "L3-GND/SIG" at 4185.41,6236.5 h60
  text "Copper" at 5115.16,6236.5 h60
  text "1.20mil" at 5974.92,6236.5 h60
  text "8" at 3775.5,6116.5 h60
  text "Dielectric3" at 4185.41,6116.5 h60
  text "370HR" at 5115.16,6116.5 h60
  text "28.00mil" at 5974.92,6116.5 h60
  text "4.36" at 6624.76,6116.5 h60
  text "9" at 3775.5,5996.5 h60
  text "L4-GND/SIG" at 4185.41,5996.5 h60
  text "Copper" at 5115.16,5996.5 h60
  text "1.20mil" at 5974.92,5996.5 h60
  text "10" at 3775.5,5876.5 h60
  text "Dielectric4" at 4185.41,5876.5 h60
  text "370HR" at 5115.16,5876.5 h60
  text "5.90mil" at 5974.92,5876.5 h60
  text "3.9" at 6624.76,5876.5 h60
  text "11" at 3775.5,5756.5 h60
  text "L5-GND2" at 4185.41,5756.5 h60
  text "Copper" at 5115.16,5756.5 h60
  text "1.20mil" at 5974.92,5756.5 h60
  text "12" at 3775.5,5636.5 h60
  text "Dielectric5" at 4185.41,5636.5 h60
  text "370HR" at 5115.16,5636.5 h60
  text "4.00mil" at 5974.92,5636.5 h60
  text "4.26" at 6624.76,5636.5 h60
  text "13" at 3775.5,5516.5 h60
  text "BOTTOM" at 4185.41,5516.5 h60
  text "Copper" at 5115.16,5516.5 h60
  text "1.60mil" at 5974.92,5516.5 h60
  text "14" at 3775.5,5396.5 h60
  text "Bottom Solder" at 4185.41,5396.5 h60
  text "Solder Resist" at 5115.16,5396.5 h60
  text "0.80mil" at 5974.92,5396.5 h60
  text "0" at 6624.76,5396.5 h60
  text "15" at 3775.5,5276.5 h60
  text "Bottom Overlay" at 4185.41,5276.5 h60
Mechanical 14:
  text "NOTES: UNLESS OTHERWISE SPECIFIED." at 3982.31,2648.8 h60
  text "1. ALL VIAS ARE TENTED ON BOTH SIDES UNLESS SOLDERMASK OPENED IN GERBER." at 3986.8,2136.01 h60
  text "2. ALL VIAS ON PAD INCLUDING BGA AREA SHOULD BE FILLED WITH NON CONDUCTIVE EPOXY AND SURFACE SHOULD BE FLAT" at 3988.14,1986.34 h60
  text "BGA AREA VIAS SHOULD BE CAPPED WITH COPPER PLATING TO ENSURE FLAT SURFACE" at 4158.14,1879.34 h60
  text "REFER VIA FILL DOCUMENT TO IDENTIFY THE VIAS TO BE FILLED" at 4158.14,1775.34 h60
  text "FLATNESS TOLERANCE FOR VIA ON PADS: +0.000 /- 0.001 INCHES ON BOTH SIDES." at 4158.14,1666.34 h60
  text "3. MANUFACTURER'S IDENTIFICATION,DATECODE LETTER SHALL BE SILKSCREENED ON SOLDER SIDE" at 3974.61,1494.94 h60
  text "OF THE BOARD." at 4144.61,1381.94 h60
  text "4. TRACE WIDTH SHOULD BE ACCURATELY ETCHED. MAX TOLERANCE +/- 1 MIL" at 3974.61,1267.94 h60
  text "5. REFER STACKUP DOCUMENT FOR IMPEDANCE CONTROL TRACES ON LAYER 1." at 3960,1134.48 h60
  text "50 OHM SINGLE ENDED AND 100 OHM DIFFERENTIAL IMPEDANCE CONTROL TRACES." at 4071,1023 h60
  text "6. SOLDER MASK OPENING IS KEPT SAME SIZE AS PAD (1:1)." at 3980,876.35 h60
  text "THE MANUFACTURER IS REQUESTED TO RESIZE IT AS PER THEIR SOLDERMASK TOLERANCE EXCEPT NPTH DRILL AND FIDUCIALS." at 4090,722.46 h60
Mechanical 16:
  lines w0.16: -48930.49,-49088.31 cw(c-48930.49,-49085.55) -48933.25,-49085.55 -48933.25,-48990.08 cw(c-48930.49,-48990.08) -48930.49,-48987.32
  lines w0.79: -48810.48,-49133.52 -48810.48,-49166 -48672.68,-49166 -48672.68,-49133.52 ; -48769.14,-49166 -48769.14,-49133.52
FAB_DWG:
  lines w1: 36.77,6724.39 36.77,6736.82 49.2,6749.26 36.77,6761.69 36.77,6774.12 49.2,6774.12 61.63,6761.69 74.07,6774.12 86.5,6774.12 86.5,6761.69 74.07,6749.26 86.5,6736.82 86.5,6724.39 74.07,6724.39 61.63,6736.82 49.2,6724.39 36.77,6724.39 ; 46.72,6734.34 46.72,6741.8 54.17,6749.26 46.72,6756.71 46.72,6764.17 54.17,6764.17 61.63,6756.71 69.09,6764.17 76.55,6764.17 76.55,6756.71 69.09,6749.26 76.55,6741.8 76.55,6734.34 69.09,6734.34 61.63,6741.8 54.17,6734.34 46.72,6734.34 ; 3373.77,4088.82 3386.2,4088.82 3386.2,4076.39 3411.07,4076.39 3411.07,4088.82 3423.5,4088.82 3423.5,4113.69 3411.07,4113.69 3411.07,4126.12 3386.2,4126.12 3386.2,4113.69 3373.77,4113.69 3373.77,4088.82 ; 3383.72,4093.8 3391.17,4093.8 3391.17,4086.34 3406.09,4086.34 3406.09,4093.8 3413.55,4093.8 3413.55,4108.71 3406.09,4108.71 3406.09,4116.17 3391.17,4116.17 3391.17,4108.71 3383.72,4108.71 3383.72,4093.8
  lines w15: -31,6828.82 2620.32,6828.82 ; 320.66,5187.83 320.66,6978 ; 588.26,5187.83 588.26,6978 ; 1187.33,5187.83 1187.33,6978 ; 1760.14,5187.83 1760.14,6978 ; 2032.61,5187.83 2032.61,6978 ; 3306,4180.82 5765.7,4180.82 ; 3657.66,4031.64 3657.66,4330 ; 3925.26,4031.64 3925.26,4330 ; 4468.22,4031.64 4468.22,4330 ; 4905.52,4031.64 4905.52,4330 ; 5177.99,4031.64 5177.99,4330 ; -31,5187.83 2620.32,5187.83 2620.32,6978 -31,6978 -31,5187.83 ; 3306,4031.64 5765.7,4031.64 5765.7,4330 3306,4330 3306,4031.64
  text "Symbol" at 58.51,6873.57 h72
  text "Count" at 365.41,6873.57 h72
  text "Hole Size" at 633.02,6873.57 h72
  text "Hole Length" at 1232.08,6873.57 h72
  text "Plated" at 1804.89,6873.57 h72
  text "Drill Layer Pair" at 2077.36,6873.57 h72
  text "9" at 365.41,6724.39 h60
  text "7.87mil (0.200mm)" at 633.02,6724.39 h60
  text "PTH" at 1804.89,6724.39 h60
  text "0.00mil (0.000mm)" at 2077.36,6724.39 h60
  text "A" at 49.2,6587.64 h49.73
  text "1046" at 365.41,6575.21 h60
  text "12.20mil (0.310mm)" at 633.02,6575.21 h60
  text "PTH" at 1804.89,6575.21 h60
  text "0.00mil (0.000mm)" at 2077.36,6575.21 h60
  text "J" at 49.2,6438.46 h49.73
  text "2" at 365.41,6426.03 h60
  text "23.62mil (0.600mm)" at 633.02,6426.03 h60
  text "51.18mil (1.300mm)" at 1232.08,6426.03 h60
  text "PTH" at 1804.89,6426.03 h60
  text "0.00mil (0.000mm)" at 2077.36,6426.03 h60
  text "B" at 49.2,6289.28 h49.73
  text "2" at 365.41,6276.85 h60
  text "33.46mil (0.850mm)" at 633.02,6276.85 h60
  text "PTH" at 1804.89,6276.85 h60
  text "0.00mil (0.000mm)" at 2077.36,6276.85 h60
  text "I" at 49.2,6140.1 h49.73
  text "3" at 365.41,6127.67 h60
  text "39.37mil (1.000mm)" at 633.02,6127.67 h60
  text "PTH" at 1804.89,6127.67 h60
  text "0.00mil (0.000mm)" at 2077.36,6127.67 h60
  text "C" at 49.2,5990.92 h49.73
  text "10" at 365.41,5978.49 h60
  text "40.00mil (1.016mm)" at 633.02,5978.49 h60
  text "PTH" at 1804.89,5978.49 h60
  text "0.00mil (0.000mm)" at 2077.36,5978.49 h60
  text "D" at 49.2,5841.74 h49.73
  text "2" at 365.41,5829.31 h60
  text "40.16mil (1.020mm)" at 633.02,5829.31 h60
  text "NPTH" at 1804.89,5829.31 h60
  text "0.00mil (0.000mm)" at 2077.36,5829.31 h60
  text "E" at 49.2,5692.56 h49.73
  text "3" at 365.41,5680.12 h60
  text "40.16mil (1.020mm)" at 633.02,5680.12 h60
  text "PTH" at 1804.89,5680.12 h60
  text "0.00mil (0.000mm)" at 2077.36,5680.12 h60
  text "F" at 49.2,5543.38 h49.73
  text "3" at 365.41,5530.94 h60
  text "47.24mil (1.200mm)" at 633.02,5530.94 h60
  text "PTH" at 1804.89,5530.94 h60
  text "0.00mil (0.000mm)" at 2077.36,5530.94 h60
  text "G" at 49.2,5394.19 h49.73
  text "2" at 365.41,5381.76 h60
  text "157.48mil (4.000mm)" at 633.02,5381.76 h60
  text "PTH" at 1804.89,5381.76 h60
  text "0.00mil (0.000mm)" at 2077.36,5381.76 h60
  text "H" at 49.2,5245.01 h49.73
  text "5" at 365.41,5232.58 h60
  text "160.00mil (4.064mm)" at 633.02,5232.58 h60
  text "NPTH" at 1804.89,5232.58 h60
  text "0.00mil (0.000mm)" at 2077.36,5232.58 h60
  text "FOR 7.87MIL DRILL +0/-7.87MIL" at 220.6,5050 h60
  text "FOR 12.20 MIL DRILL +0/-12.20MIL" at 220.52,4945.19 h60
  text "FOR PTH +/-3MIL" at 224.82,4824.79 h60
  text "FOR NPTH +/-2MIL" at 224.82,4670 h60
  text "Symbol" at 3395.51,4225.57 h72
  text "Count" at 3702.41,4225.57 h72
  text "Hole Size" at 3970.02,4225.57 h72
  text "Hole Length" at 4512.97,4225.57 h72
  text "Plated" at 4950.27,4225.57 h72
  text "Drill Layer Pair" at 5222.74,4225.57 h72
  text "700" at 3702.41,4076.39 h60
  text "5.90mil (0.150mm)" at 3970.02,4076.39 h60
  text "PTH" at 4950.27,4076.39 h60
  text "0.00mil (0.000mm)" at 5222.74,4076.39 h60
  text "FOR 5.90 MIL DRILL +0/-5.90MIL" at 3460,3900 h60
  text "FAB_DWG" at -1322.95,-1032.44 h60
